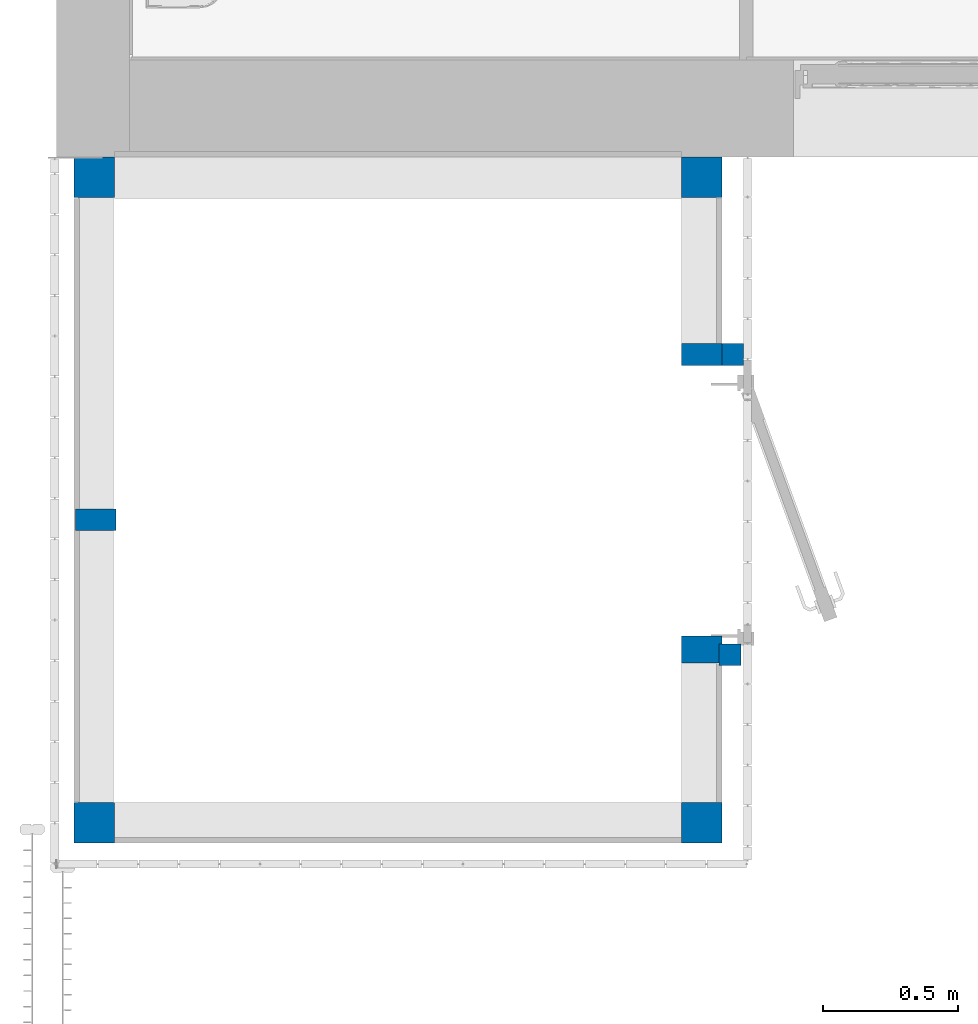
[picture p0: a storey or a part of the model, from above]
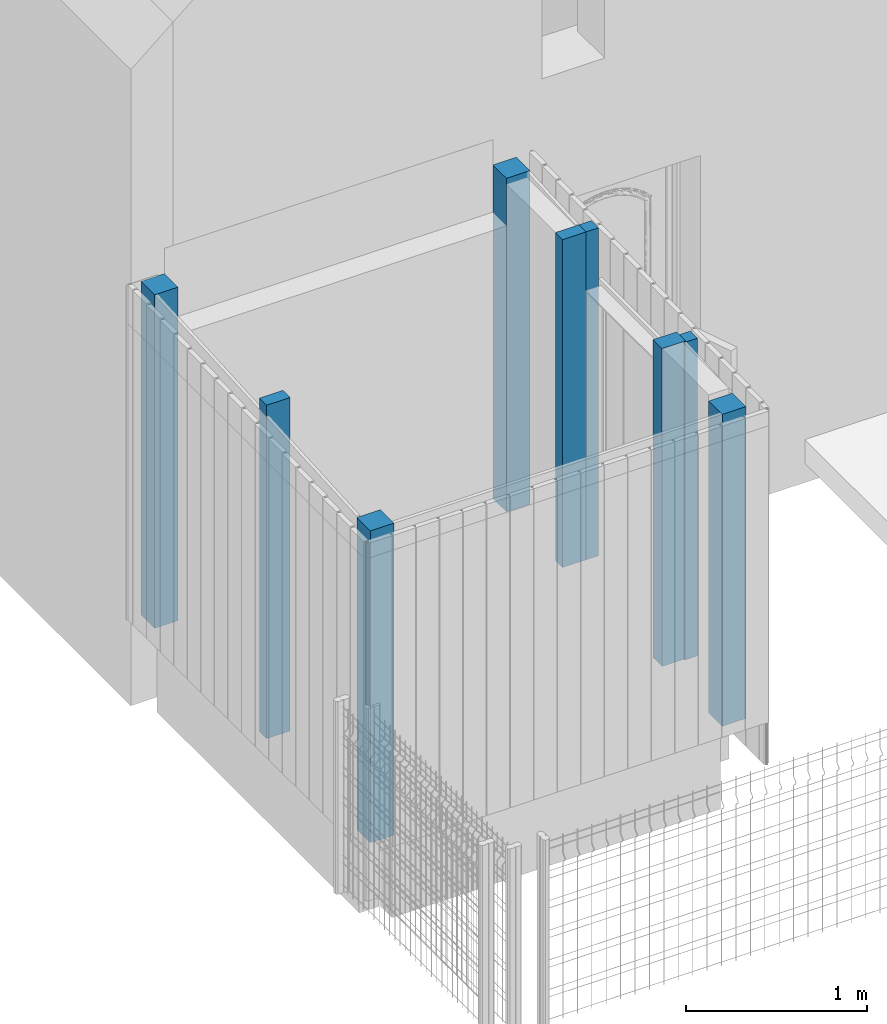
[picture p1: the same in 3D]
Properties of the parts of a building model (IFC2X3)

# File
Description: ViewDefinition [CoordinationView_V2.0]
File name: Affaire n°19.172
Time: 2022-11-25T11:16:12
Written by: The EXPRESS Data Manager Version 5.02.0100.07 : 28 Aug 2013
Made in: 21.0.0.383 - Exporter 21.0.0.383 - Interface utilisateur alternative 21.0.0.383
Comment: STEP Physical File produced by: The EXPRESS Data Manager Version 5.02.0100.07 : 28 Aug 2013 * Module: EDMstepFileFactory/EDMstandAlone * Creation date: Fri Nov 25 11:16:12 2022 * Host: LGB7831 * Database: C:\Users\ROMAIN~1.RIB\AppData\Local\Temp\cd2d28db-151a-48f7-b0e3-fceab26f3357\acbd01e7-b79b-4e43-bebc-0b0fced7cc93\ifc * Database version: 5507 * Database creation date: Fri Nov 25 11:14:17 2022 * Schema: IFC2X3 * Model: DataRepository.ifc * Model creation date: Fri Nov 25 11:14:17 2022 * Header model: DataRepository.ifc_HeaderModel * Header model creation date: Fri Nov 25 11:14:17 2022 * EDMuser: sdai-user * EDMgroup: sdai-group * License ID and type: 5605 : Permanent license. Expiry date: * EDMstepFileFactory options: 020000

# IfcProject, Affaire n°19.172
LongName: Construction de 4 Maisons Individuelles; Phase: Construction

# IfcSite, Surface:931155
RefLatitude: 48, 52, 0, 117187; RefLongitude: 2, 19, 59, 880409; RefElevation: 0 m

# IfcBuilding
Pset_BuildingCommon - NumberOfStoreys: 3

# IfcBuildingStorey: Niveau:Ligne du Niveau (3)
Name | LongName | Elevation (m)
01 RDC | 01 RDC | -1.94916e-14
02 ETG | 02 ETG | 2.72
03 Goutière | 03 Goutière | 3.91

# IfcBuildingElementProxy: Electrical_Distribution_Legrand_Coffrets-isolants-Drivia-pour-de-tableaux-electriques-de-1-a-4-rangees-de-18-modules_FR:coffret DRIVIA 18 modules 1 rangée, Electrical_Distribution_Legrand_Coffrets-isolants-Drivia-pour-de-tableaux-electriques-de-1-a-4-rangees-de-18-modules_FR:coffret DRIVIA 18 modules 1 rangée, 0 V, Monophasé Phase, 2 Fils:699805
In: 01 RDC
Type - Material: Zone d'installation
Type - Pset_BuildingElementProxyCommon - Reference: coffret DRIVIA 18 modules 1 rangée
Type - Pset_ManufacturerTypeInformation - Manufacturer: Legrand
Type - Pset_QuantityTakeOff - Reference: coffret DRIVIA 18 modules 1 rangée
Pset_BuildingElementProxyCommon - sets with these values: 2

# IfcBuildingElementProxy: Frogo 2:Default, Frogo 2:Default:514300
In: 01 RDC
Type - Material: AEG FS Fridge Freezer Bottom Freezer Silver+Stainless Steel Door with Antifingerprint 595 2005 - AEG_FS_Fridge_Freezer_Bottom_Freezer_Silver_Stainless_Steel_Door_with_Antifingerprint_595_2005 - Stainless_Steel
Type - Pset_BuildingElementProxyCommon - Reference: Default
Type - Pset_QuantityTakeOff - Reference: Default
Type - Pset_ProvisionForVoid - Width: 181.356 m; Height: 197.206 m; Depth: 611.124 m
Material: AEG FS Fridge Freezer Bottom Freezer Silver+Stainless Steel Door with Antifingerprint 595 2005 - AEG_FS_Fridge_Freezer_Bottom_Freezer_Silver_Stainless_Steel_Door_with_Antifingerprint_595_2005 - Stainless_Steel, AEG FS Fridge Freezer Bottom Freezer Silver+Stainless Steel Door with Antifingerprint 595 2005 - AEG_FS_Fridge_Freezer_Bottom_Freezer_Silver_Stainless_Steel_Door_with_Antifingerprint_595_2005 - Top_AEG FS Fridge_Freezer Bottom Freezer Silver+Stainless Steel Door with Antifingerprint 59
Pset_BuildingElementProxyCommon - sets with these values: 2

# IfcBuildingElementProxy: Haie 0.25:Haie 0.25 (11)
In: 01 RDC
Type - Pset_BuildingElementProxyCommon - Reference: Haie 0.25
Type - Pset_QuantityTakeOff - Reference: Haie 0.25
Pset_BuildingElementProxyCommon - sets with these values: 2
Name (Haie 0.25:Haie 0.25:...)
514370
514374
514375
514376
514377
514378
514379
514380
514381
514382
514383

# IfcBuildingElementProxy: LL:Default, LL:Default:514303
In: 01 RDC
Type - Material: AEG Free Standing Washer HEC 60 White - AEG_Free_Standing_Washer_HEC_60_White - log_23
Type - Pset_BuildingElementProxyCommon - Reference: Default
Type - Pset_QuantityTakeOff - Reference: Default
Type - Pset_ProvisionForVoid - Width: 182.88 m; Height: 259.08 m; Depth: 184.404 m
Material: AEG Free Standing Washer HEC 60 White - AEG_Free_Standing_Washer_HEC_60_White - log_23, AEG Free Standing Washer HEC 60 White - AEG_Free_Standing_Washer_HEC_60_White - White, AEG Free Standing Washer HEC 60 White - AEG_Free_Standing_Washer_HEC_60_White - Gray, AEG Free Standing Washer HEC 60 White - AEG_Free_Standing_Washer_HEC_60_White - Top_AEG Free_Standing Washer HEC 60 White, AEG Free Standing Washer HEC 60 White - AEG_Free_Standing_Washer_HEC_60_White - Steel, AEG Free Standing Washer HEC 60 White - AEG_Free_Standing_Washer_HEC_60_White - Bottom_AEG Free_Standing Washer HEC 60 White, AEG Free Standing Washer HEC 60 White - AEG_Free_Standing_Washer_HEC_60_White - Black, AEG Free Standing Washer HEC 60 White - AEG_Free_Standing_Washer_HEC_60_White - Dark Gray
Pset_BuildingElementProxyCommon - sets with these values: 2

# IfcBuildingElementProxy: LV:Default (2)
In: 01 RDC
Type - Material: AEG FSBU 60 Dishwasher White - AEG_FSBU_60_Dishwasher_White - White
Type - Pset_BuildingElementProxyCommon - Reference: Default
Type - Pset_QuantityTakeOff - Reference: Default
Material: AEG FSBU 60 Dishwasher White - AEG_FSBU_60_Dishwasher_White - White, AEG FSBU 60 Dishwasher White - AEG_FSBU_60_Dishwasher_White - Top_AEG FSBU 60 Dishwasher White, AEG FSBU 60 Dishwasher White - AEG_FSBU_60_Dishwasher_White - Bottom_AEG FSBU 60 Dishwasher White
Pset_BuildingElementProxyCommon - sets with these values: 2
Name (LV:Default:...)
514301
550132

# IfcBuildingElementProxy: Meuble évier:Meuble évier, Meuble évier:Meuble évier:514305
In: 01 RDC
Type - Material: CabinetFinish
Type - Pset_BuildingElementProxyCommon - Reference: Meuble évier
Type - Pset_QuantityTakeOff - Reference: Meuble évier
Material: CabinetFinish, Default metal, EquipSpace
Pset_BuildingElementProxyCommon - sets with these values: 2
Pset_ProvisionForVoid - Width: 0.56515 m; Height: 0.6096 m; Depth: 0.56515 m

# IfcBuildingElementProxy: Portail pivotant treillis OOBAMBOO:2 vantaux - 3355mm x 1100mm, Portail pivotant treillis OOBAMBOO:2 vantaux - 3355mm x 1100mm:514336
In: 01 RDC
Type - Material: NORMACLO Métal, NORMACLO Butée
Type - Pset_BuildingElementProxyCommon - Reference: 2 vantaux - 3355mm x 1100mm
Type - Pset_ManufacturerTypeInformation - Manufacturer: NORMACLO
Type - Pset_QuantityTakeOff - Reference: 2 vantaux - 3355mm x 1100mm
Material: NORMACLO Métal
Pset_BuildingElementProxyCommon - sets with these values: 2

# IfcBuildingElementProxy: Tiles_Swiss Krono_Placeholder:Tiles_Swiss Krono_Placeholder (5)
In: 01 RDC
Type - Material: Bois - Swiss Krono - OSB 3 - Panneau Anti-Termites 2500x1250x13mm
Type - Pset_BuildingElementProxyCommon - Reference: Tiles_Swiss Krono_Placeholder
Type - Pset_QuantityTakeOff - Reference: Tiles_Swiss Krono_Placeholder
Pset_BuildingElementProxyCommon - sets with these values: 2
Name (Tiles_Swiss Krono_Placeholder:Tiles_Swiss Krono_Placeholder:...) | Width (m) = Height (m) | Depth (m)
908347 | 2.235 | 0.13
917175 | 0.5398 | 0.13
924072 | 0.129219 | 2.095
924377 | 0.5152 | 0.13
1074472 | 0.1525 | 2.095

# IfcColumn: Bois - Bois de construction de dimensions courantes:Poteau bois 15*08 (2)
In: 01 RDC
Type - PredefinedType: COLUMN; Material: Bois - Pin
Type - Pset_ColumnCommon - IsExternal: no; LoadBearing: yes; Reference: Poteau bois 15*08
Type - Pset_QuantityTakeOff - Reference: Poteau bois 15*08
Type - Pset_ReinforcementBarPitchOfColumn - Reference: Poteau bois 15*08
Pset_QuantityTakeOff - sets with these values: 2
Name (Bois - Bois de construction de dimensions courantes:Poteau bois 15*08:...)
514329
910802

# IfcColumn: Bois - Bois de construction de dimensions courantes:Poteau bois 15*10, Bois - Bois de construction de dimensions courantes:Poteau bois 15*10:514325
In: 01 RDC
Type - PredefinedType: COLUMN; Material: Bois - Pin
Type - Pset_ColumnCommon - IsExternal: no; LoadBearing: yes; Reference: Poteau bois 15*10
Type - Pset_QuantityTakeOff - Reference: Poteau bois 15*10
Type - Pset_ReinforcementBarPitchOfColumn - Reference: Poteau bois 15*10
Pset_QuantityTakeOff - sets with these values: 2

# IfcColumn: Bois - Bois de construction de dimensions courantes:Poteau bois 15*15 (4)
In: 01 RDC
Type - PredefinedType: COLUMN; Material: Bois - Pin
Type - Pset_ColumnCommon - IsExternal: no; LoadBearing: yes; Reference: Poteau bois 15*15
Type - Pset_QuantityTakeOff - Reference: Poteau bois 15*15
Type - Pset_ReinforcementBarPitchOfColumn - Reference: Poteau bois 15*15
Pset_QuantityTakeOff - sets with these values: 2
Name (Bois - Bois de construction de dimensions courantes:Poteau bois 15*15:...)
514268
514270
514272
514274

# IfcColumn: Bois - Bois de construction de dimensions courantes:Poteau bois 6*6 (2)
In: 01 RDC
Type - PredefinedType: COLUMN; Material: Bois - Pin
Type - Pset_ColumnCommon - IsExternal: no; LoadBearing: yes; Reference: Poteau bois 6*6
Type - Pset_QuantityTakeOff - Reference: Poteau bois 6*6
Type - Pset_ReinforcementBarPitchOfColumn - Reference: Poteau bois 6*6
Pset_QuantityTakeOff - sets with these values: 2
Name (Bois - Bois de construction de dimensions courantes:Poteau bois 6*6:...)
514327
514331

# IfcCovering: Plafond composé:Plafond 200 + 100 + B.A13 (6)
In: 02 ETG
Type - PredefinedType: CEILING
Type - Pset_CoveringCommon - Reference: Plafond 200 + 100 + B.A13; TotalThickness: 0.31 m
Type - Pset_QuantityTakeOff - Reference: Plafond 200 + 100 + B.A13
Material: Isolant - laine minérale 0.1 m, Maçonnerie - Isolant 0.2 m, Placoplâtre de gypse 0.01 m
Pset_CoveringCommon - Finish: Placoplâtre de gypse;
Name (Plafond composé:Plafond 200 + 100 + B.A13:...)
679123
679951
680673
681739
682132
682653

# IfcCurtainWall: Mur-rideau:1m x 2m (3)
In: 01 RDC
Type - Pset_CurtainWallCommon - IsExternal: no; Reference: 1m x 2m
Type - Pset_QuantityTakeOff - Reference: 1m x 2m
Name (Mur-rideau:1m x 2m:...)
514333
514335
918926

# IfcDistributionPort (12)
Description: Flow
Name | FlowDirection
Port_514301 | SOURCEANDSINK
Port_514301 | SOURCE
Port_514301 | SINK
Port_514303 | SINK
Port_514303 | SOURCE
Port_514303 | SOURCEANDSINK
2 x Port_514304 | SINK
Port_550132 | SINK
Port_550132 | SOURCEANDSINK
Port_550132 | SOURCE
Port_699805 | SOURCEANDSINK

# IfcDoor: Doors_Sliding_PIERRET_Porte-Fenetre_Coulissante_2V:2400 x 2150 mm, Doors_Sliding_PIERRET_Porte-Fenetre_Coulissante_2V:2400 x 2150 mm:853128
In: 01 RDC
Type - OperationType: DOUBLE_DOOR_SLIDING; ParameterTakesPrecedence: no; Sizeable: no; Classification: B2030100 Glazed Doors & Entrances (Uniformat); Material: RAL_7M16ST (2)
Type - Doors_Sliding_PIERRET_Porte-Fenetre_Coulissante_2V:2400 x 2150 mm:853128 - PanelOperation: SLIDING
Type - Pset_DoorCommon - IsExternal: no; Reference: 2400 x 2150 mm
Type - Pset_ManufacturerTypeInformation - Manufacturer: PIERRET
Type - Pset_QuantityTakeOff - Reference: 2400 x 2150 mm
OverallHeight: 2.19 m; OverallWidth: 2.48 m; Material: RAL_7M16ST, Generique - PIERRET - Blanc, Verre - PIERRET - Vitrage, Polyamide - PIERRET - Joint-Intercalaire, Generique - PIERRET - Gris
Pset_DoorCommon - IsExternal: yes

# IfcDoor: Doors_Swing_Bouvet_Single-French-Door_FR:1000 x 2150 mm - Blue (2)
In: 01 RDC
Type - ParameterTakesPrecedence: no; Sizeable: no; Classification: B2030100 (Uniformat); Material: Aluminium - BOUVET - Satiné 7016, Aluminium - BOUVET - Blanc Standard (2), Aluminium - BOUVET - Texturé 7006
Type - Pset_DoorCommon - IsExternal: no; Reference: 1000 x 2150 mm - Blue
Type - Pset_ManufacturerTypeInformation - Manufacturer: BOUVET
Type - Pset_QuantityTakeOff - Reference: 1000 x 2150 mm - Blue
OverallHeight: 2.233 m; OverallWidth: 1.267 m; Material: Aluminium - BOUVET - Blanc Standard, Aluminium - BOUVET - Satiné 7016, Glass, Aluminium - BOUVET - Anodisee
Pset_DoorCommon - IsExternal: yes
Name (Doors_Swing_Bouvet_Single-French-Door_FR:1000 x 2150 mm - Blue:...)
839372
847337

# IfcDoor: Ext. Simple:Lisse - 0.90 m x 2.15 m, Ext. Simple:Lisse - 0.90 m x 2.15 m:928771
In: 01 RDC
Type - OperationType: SINGLE_SWING_RIGHT; ParameterTakesPrecedence: no; Sizeable: no; Material: PVC - Blanc (3)
Type - Ext. Simple:Lisse - 0.90 m x 2.15 m:928771 - PanelOperation: SWINGING
Type - Pset_DoorCommon - IsExternal: no; Reference: Lisse - 0.90 m x 2.15 m; ThermalTransmittance: 5.5617 kg/K/s3
Type - Pset_QuantityTakeOff - Reference: Lisse - 0.90 m x 2.15 m
OverallHeight: 2.2 m; OverallWidth: 1 m; Material: PVC - Blanc
Pset_DoorCommon - IsExternal: yes

# IfcDoor: Int. Simple:PP (0.60 m x 0.8 m), Int. Simple:PP (0.60 m x 0.8 m):706713
In: 01 RDC
Type - ParameterTakesPrecedence: no; Sizeable: no; Material: Bois - Cadre de porte (2), Bois - Panneau de porte, Finition Peinture - Blanc satiné
Type - Pset_DoorCommon - IsExternal: no; Reference: PP (0.60 m x 0.8 m)
Type - Pset_QuantityTakeOff - Reference: PP (0.60 m x 0.8 m)
OverallHeight: 0.835 m; OverallWidth: 0.47 m; Material: Finition Peinture - Blanc satiné, Bois - Panneau de porte, Bois - Cadre de porte

# IfcDoor: Int. Simple:PP (0.73m x 2.04m), Int. Simple:PP (0.73m x 2.04m):514258
In: 01 RDC
Type - ParameterTakesPrecedence: no; Sizeable: no; Material: Finition Peinture - Blanc satiné, Bois - Panneau de porte, Bois - Cadre de porte (2)
Type - Pset_DoorCommon - IsExternal: no; Reference: PP (0.73m x 2.04m); ThermalTransmittance: 3.7021 kg/K/s3
Type - Pset_QuantityTakeOff - Reference: PP (0.73m x 2.04m)
OverallHeight: 2.075 m; OverallWidth: 0.8 m; Material: Finition Peinture - Blanc satiné, Bois - Panneau de porte, Bois - Cadre de porte

# IfcDoor: Int. Simple:PP (0.83m x 2.04m) (2)
Type - ParameterTakesPrecedence: no; Sizeable: no; Material: Bois - Cadre de porte (2), Bois - Panneau de porte, Finition Peinture - Blanc satiné
Type - Pset_DoorCommon - IsExternal: no; Reference: PP (0.83m x 2.04m); ThermalTransmittance: 3.7021 kg/K/s3
Type - Pset_QuantityTakeOff - Reference: PP (0.83m x 2.04m)
OverallHeight: 2.075 m; OverallWidth: 0.9 m; Material: Finition Peinture - Blanc satiné, Bois - Panneau de porte, Bois - Cadre de porte
Name (Int. Simple:PP (0.83m x 2.04m):...) | In
514243 | 01 RDC
732271 | 02 ETG

# IfcDoor: Int. Simple:PP (0.83m x 2.04m), Int. Simple:PP (0.83m x 2.04m):514259
In: 01 RDC
Type - ParameterTakesPrecedence: no; Sizeable: no; Material: Finition Peinture - Blanc satiné, Bois - Cadre de porte (2), Bois - Panneau de porte
Type - Pset_DoorCommon - IsExternal: no; Reference: PP (0.83m x 2.04m); ThermalTransmittance: 3.7021 kg/K/s3
Type - Pset_QuantityTakeOff - Reference: PP (0.83m x 2.04m)
OverallHeight: 2.075 m; OverallWidth: 0.9 m; Material: Finition Peinture - Blanc satiné, Bois - Panneau de porte, Bois - Cadre de porte

# IfcDoor: Int. Simple:Porte pleine parement lisse bois prépeinte (3)
In: 02 ETG
Type - ParameterTakesPrecedence: no; Sizeable: no; Material: Finition Peinture - Blanc satiné, Bois - Cadre de porte (2), Bois - Panneau de porte
Type - Pset_DoorCommon - IsExternal: no; Reference: Porte pleine parement lisse bois prépeinte
Type - Pset_QuantityTakeOff - Reference: Porte pleine parement lisse bois prépeinte
OverallHeight: 2.075 m; OverallWidth: 0.9 m; Material: Finition Peinture - Blanc satiné, Bois - Panneau de porte, Bois - Cadre de porte
Name (Int. Simple:Porte pleine parement lisse bois prépeinte:...) | Reference | sets with these values
514632 | Porte pleine parement lisse bois prépeinte | 2
514636
1084562 | Porte pleine parement lisse bois prépeinte | 2

# IfcDoor: Int. Simple:Porte pleine parement lisse bois prépeinte, Int. Simple:Porte pleine parement lisse bois prépeinte:514656
In: 02 ETG
Type - ParameterTakesPrecedence: no; Sizeable: no; Material: Finition Peinture - Blanc satiné, Bois - Panneau de porte, Bois - Cadre de porte (2)
Type - Pset_DoorCommon - IsExternal: no; Reference: Porte pleine parement lisse bois prépeinte
Type - Pset_QuantityTakeOff - Reference: Porte pleine parement lisse bois prépeinte
OverallHeight: 2.075 m; OverallWidth: 0.9 m; Material: Finition Peinture - Blanc satiné, Bois - Panneau de porte, Bois - Cadre de porte

# IfcDoor: K-LINE RENO-tunnel Porte Entrée 1vt - Créative Arc:K-LINE RENO-tunnel Porte Entrée 1vt - Créative Arc, K-LINE RENO-tunnel Porte Entrée 1vt - Créative Arc:K-LINE RENO-tunnel Porte Entrée 1vt - Créative Arc:878110
In: 01 RDC
Type - ParameterTakesPrecedence: no; Sizeable: no; Classification: B2030110 Exterior Glazed Doors - Aluminum (Uniformat); Material: K.Line Couleur Bleu Clair (2023 T) - ST, K.Line Intemporel Blanc satiné (9016 S) - KQ, Verre sablé
Type - Pset_DoorCommon - IsExternal: no; Reference: K-LINE RENO-tunnel Porte Entrée 1vt - Créative Arc
Type - Pset_ManufacturerTypeInformation - Manufacturer: K.LINE
Type - Pset_QuantityTakeOff - Reference: K-LINE RENO-tunnel Porte Entrée 1vt - Créative Arc
OverallHeight: 2.15 m; OverallWidth: 0.91 m; Material: Verre sablé, K.Line Intemporel Blanc satiné (9016 S) - KQ, K.Line Couleur Bleu Clair (2023 T) - ST, Acier inoxydable AISI 304, K.Line Tendance Gris sablé (2900) - NX, K.Line Vintage Anodisé Argent - AC
Pset_DoorCommon - IsExternal: yes

# IfcDoor: Placard coulissante - 2 panneaux:Placard coulissante - 2 panneaux (5)
In: 02 ETG
Type - OperationType: SLIDING_TO_RIGHT; ParameterTakesPrecedence: no; Sizeable: no; Material: Placard - Profil, Placard - Encadrement, Placard - Porte
Type - Placard coulissante - 2 panneaux:Placard coulissante - 2 panneaux:514622 - PanelOperation: SLIDING
Type - Pset_DoorCommon - IsExternal: no; Reference: Placard coulissante - 2 panneaux; ThermalTransmittance: 3.7021 kg/K/s3
Type - Pset_QuantityTakeOff - Reference: Placard coulissante - 2 panneaux
OverallHeight: 1.98 m; OverallWidth: 1.2 m
Name (Placard coulissante - 2 panneaux:Placard coulissante - 2 panneaux:...)
514622 | Pset_OpeningElementCommon - Reference: Placard coulissante - 2 panneaux; sets with these values: 2
514652
514653
514654
514655

# IfcDoor: Volet coulissant ONDEA 1 vantail simple rail:Bois "CONCEPTION WESTERN UNIQUEMENT" (3)
In: 02 ETG
Type - ParameterTakesPrecedence: no; Sizeable: no; Material: FF bois RAL 5014
Type - Pset_DoorCommon - IsExternal: no; Reference: Bois "CONCEPTION WESTERN UNIQUEMENT"
Type - Pset_ManufacturerTypeInformation - Manufacturer: France Fermetures
Type - Pset_QuantityTakeOff - Reference: Bois "CONCEPTION WESTERN UNIQUEMENT"
OverallHeight: 3.756 m; OverallWidth: 2.59 m
Name (Volet coulissant ONDEA 1 vantail simple rail:Bois "CONCEPTION WESTERN UNIQUEMENT":...)
931392 | Pset_DoorCommon - IsExternal: yes
1081363
1081364

# IfcFlowTerminal: Bac à douche rectangulaire:120 x 90 cm, Bac à douche rectangulaire:120 x 90 cm:514308
In: 01 RDC
Type - Material: Acrylique - Blanc, Métal - Chrome
Type - Pset_QuantityTakeOff - Reference: 120 x 90 cm
Material: Métal - Chrome, Acrylique - Blanc
Pset_DistributionFlowElementCommon - Reference: 120 x 90 cm; sets with these values: 3

# IfcFlowTerminal: Baignoire rectangulaire - Mur:Baignoire rectangulaire - Mur, Baignoire rectangulaire - Mur:Baignoire rectangulaire - Mur:514646
In: 02 ETG
Type - Material: Céramique - Blanche
Type - Pset_QuantityTakeOff - Reference: Baignoire rectangulaire - Mur
Pset_DistributionFlowElementCommon - Reference: Baignoire rectangulaire - Mur; sets with these values: 3

# IfcFlowTerminal: Cuvette réservoir:Cuvette réservoir (2)
Type - Material: Stratifié - Lin, Mat, Porcelaine - Lin
Type - Pset_QuantityTakeOff - Reference: Cuvette réservoir
Material: Porcelaine - Lin, Stratifié - Lin, Mat
Pset_DistributionFlowElementCommon - Reference: Cuvette réservoir; sets with these values: 3
Name (Cuvette réservoir:Cuvette réservoir:...) | In
514306 | 01 RDC
514662 | 02 ETG

# IfcFlowTerminal: Douche - 02:Douche - 02, Douche - 02:Douche - 02:514309
In: 01 RDC
Type - Material: Métal - Chrome poli
Type - Pset_QuantityTakeOff - Reference: Douche - 02
Pset_DistributionFlowElementCommon - Reference: Douche - 02; sets with these values: 3

# IfcFlowTerminal: Evier double:840mm x 560 mm, Evier double:840mm x 560 mm:514304
In: 01 RDC
Type - Material: f26d4e4b_a025_4dbf_b085_30ed485788cf
Type - Pset_QuantityTakeOff - Reference: 840mm x 560 mm
Pset_DistributionFlowElementCommon - Reference: 840mm x 560 mm; sets with these values: 2

# IfcFlowTerminal: Lavabo sur pied:Lavabo sur pied (2)
Type - Material: Métal - Chrome, Porcelaine - Lin (2)
Type - Pset_QuantityTakeOff - Reference: Lavabo sur pied
Material: Porcelaine - Lin, Métal - Chrome
Pset_DistributionFlowElementCommon - Reference: Lavabo sur pied; sets with these values: 3
Name (Lavabo sur pied:Lavabo sur pied:...) | In
514307 | 01 RDC
514644 | 02 ETG

# IfcFlowTerminal: Robinet mural - Douche:#01, Robinet mural - Douche:#01:514310
In: 01 RDC
Type - Material: Métal - Chrome
Type - Pset_QuantityTakeOff - Reference: #01
Pset_DistributionFlowElementCommon - Reference: #01; sets with these values: 3

# IfcFurnishingElement: Armoire de salle de bain - 1 porte miroir:40 x 24 x 64 cm - Blanc, Armoire de salle de bain - 1 porte miroir:40 x 24 x 64 cm - Blanc:514645
In: 02 ETG
Type - Material: Aggloméré - Blanc, Métal - Chrome
Type - Pset_QuantityTakeOff - Reference: 40 x 24 x 64 cm - Blanc
Material: Métal - Chrome, Aggloméré - Blanc

# IfcFurnishingElement: Lit à tête en bois:2000mm x 2100mm (4)
Type - Material: Bois - Teck, Métal - Chrome, Textile - Bleu pâle
Type - Pset_QuantityTakeOff - Reference: 2000mm x 2100mm
Material: Textile - Bleu pâle, Bois - Teck, Métal - Chrome
Name (Lit à tête en bois:2000mm x 2100mm:...) | In
514311 | 01 RDC
514641 | 02 ETG
514642 | 02 ETG
514643 | 02 ETG

# IfcMember: Meneau circulaire:R-30 mm (112)
In: 01 RDC
Type - PredefinedType: MULLION; Material: Aluminium - Vert
Type - Pset_MemberCommon - IsExternal: no; Reference: R-30 mm
Type - Pset_QuantityTakeOff - Reference: R-30 mm
Name (Meneau circulaire:R-30 mm:...) | Span (m)
514448 | 2
514449 | 0.399226
514452 | 0.558478
514453 | 2
514456 | 2
514457 | 2
514458 | 0.549456
514459 | 0.540282
514460 | 2
514461 | 2
514462 | 2
514463 | 0.353584
514464 | 0.34441
514465 | 0.335236
902583 | 0.531107
902584 | 0.521933
902585 | 0.512759
903007 | 0.326061
903008 | 0.316887
903009 | 0.307712
903010 | 2
903011 | 2
903012 | 2
903013 | 2
903014 | 2
903016 | 0.448538
903017 | 0.439364
903018 | 0.430189
903019 | 0.421015
903020 | 0.41184
911406 | 2
911407 | 0.402666
929272 | 2
929273 | 0.15
929274 | 0.15
929275 | 2
514527 | 2
514528 | 0.098614
514552 | 0.258248
514553 | 2
514554 | 2
514555 | 2
514556 | 2
514557 | 2
514558 | 2
514559 | 2
514560 | 2
514561 | 0.199685
514562 | 0.20886
514563 | 0.218034
514564 | 0.227208
514565 | 0.236383
514566 | 0.245557
514567 | 0.254732
514669 | 2
514670 | 0.190511
902988 | 2
902989 | 2
902990 | 2
902991 | 2
902992 | 2
902993 | 2
902994 | 2
902995 | 0.181336
902996 | 0.172162
902997 | 0.162988
902998 | 0.153813
902999 | 0.144639
903000 | 0.135464
903001 | 0.12629
912984 | 2
912985 | 0.117116
926241 | 2
926242 | 0.107941
918928 | 2
918929 | 0.0992256
918955 | 2
918956 | 2
918957 | 2
918958 | 2
918959 | 2
918960 | 2
918961 | 2
918984 | 2
919010 | 2
919011 | 2
919012 | 2
919013 | 2
919014 | 2
919015 | 2
919016 | 2
919057 | 2
928646 | 2
933554 | 0.0992256
933555 | 2
933556 | 0.0992256
933557 | 0.0992256
933558 | 0.0992256
933559 | 0.0992256
933560 | 0.0992256
933561 | 0.0992256
933562 | 0.0992256
933563 | 0.0992256
933564 | 0.0992256
933565 | 0.0992256
933566 | 0.0992256
933567 | 0.0992256
933568 | 0.0992256
933569 | 0.0992256
933570 | 0.0992256
933571 | 0.0992256
933572 | 0.0992256

# IfcOpeningElement: Opening (27)
Name | In
Mur de base:Ext. Enduit 2 + Parpaing 20 + Isolant 14:514209:1 | 01 RDC | Pset_OpeningElementCommon - Reference: Ext. Enduit 2 + Parpaing 20 + Isolant 14; sets with these values: 2
Mur de base:Ext. Enduit 2 + Parpaing 20 + Isolant 14:514209 | 01 RDC | Pset_OpeningElementCommon - Reference: Ext. Enduit 2 + Parpaing 20 + Isolant 14; sets with these values: 2
Int. Simple:Porte pleine parement lisse bois prépeinte:1084562:1 | 02 ETG
Int. Simple:Porte pleine parement lisse bois prépeinte:514656:1 | 02 ETG
Placard coulissante - 2 panneaux:Placard coulissante - 2 panneaux:514652:1 | 02 ETG
Placard coulissante - 2 panneaux:Placard coulissante - 2 panneaux:514653:1 | 02 ETG
Placard coulissante - 2 panneaux:Placard coulissante - 2 panneaux:514655:1 | 02 ETG
Placard coulissante - 2 panneaux:Placard coulissante - 2 panneaux:514654:1 | 02 ETG
Int. Simple:Porte pleine parement lisse bois prépeinte:514636:1 | 02 ETG
Int. Simple:Porte pleine parement lisse bois prépeinte:514632:1 | 02 ETG
Placard coulissante - 2 panneaux:Placard coulissante - 2 panneaux:514622:1 | 02 ETG
Int. Simple:PP (0.83m x 2.04m):732271:1 | 02 ETG
Mur de base:cloison séche - B.A10:514620 | 02 ETG | Pset_OpeningElementCommon - Reference: Placard coulissante - 2 panneaux; sets with these values: 2
Mur de base:cloison séche - B.A10:514621 | 02 ETG | Pset_OpeningElementCommon - Reference: Placard coulissante - 2 panneaux; sets with these values: 2
Mur de base:cloison séche - B.A10:514630 | 02 ETG | Pset_OpeningElementCommon - Reference: Porte pleine parement lisse bois prépeinte; sets with these values: 2
Mur de base:Int. Plâtre 10 mm:639148 | 01 RDC | Pset_OpeningElementCommon - Reference: Int. Plâtre 10 mm; sets with these values: 2
Mur de base:Panneau Triply 30 mm:514413 | 01 RDC
Mur de base:Int. Plâtre 10 mm:663478 | 01 RDC | Pset_OpeningElementCommon - Reference: Int. Plâtre 10 mm; sets with these values: 2
Mur de base:cloison séche - B.A10:1084497 | 02 ETG | Pset_OpeningElementCommon - Reference: Porte pleine parement lisse bois prépeinte; sets with these values: 2
4 x Mur de base:Ext. Enduit 2 + Parpaing 20 + Isolant 14:514209 | 01 RDC
Int. Simple:PP (0.60 m x 0.8 m):706713:1 | 01 RDC
Int. Simple:PP (0.83m x 2.04m):514243:1 | 01 RDC
Int. Simple:PP (0.83m x 2.04m):514259:1 | 01 RDC
Int. Simple:PP (0.73m x 2.04m):514258:1 | 01 RDC

# IfcRailing: Garde-corps:Grillage et Poteaux - 1300 mm (5)
In: 01 RDC
Material: Métal - Peinture verte
Pset_QuantityTakeOff - Reference: Grillage et Poteaux - 1300 mm
Pset_RailingCommon - IsExternal: no; Reference: Grillage et Poteaux - 1300 mm; Height: 1.2192 m
Name (Garde-corps:Grillage et Poteaux - 1300 mm:...)
452555
514339
514346
514353
514362

# IfcRoof: Toit de base:Toit - 200 mm, Toit de base:Toit - 200 mm:514601
In: 03 Goutière
Material: Toit par défaut 0.2 m
Pset_QuantityTakeOff - Reference: Toit - 200 mm
Pset_RoofCommon - IsExternal: yes; Reference: Toit - 200 mm; ProjectedArea: 67.4778 m2; TotalArea: 87.06 m2

# IfcSlab: Sol:Chappe 10 PVC-TX SELECTION 100*1500 2 (4)
Type - PredefinedType: FLOOR; Material: Maçonnerie - Béton 0.005 m
Type - Pset_QuantityTakeOff - Reference: Chappe 10 PVC-TX SELECTION 100*1500 2
Type - Pset_ReinforcementBarPitchOfSlab - Reference: Chappe 10 PVC-TX SELECTION 100*1500 2
Type - Pset_SlabCommon - IsExternal: no; Reference: Chappe 10 PVC-TX SELECTION 100*1500 2
Pset_QuantityTakeOff - sets with these values: 2
Pset_SlabCommon - PitchAngle: 0 deg; LoadBearing: no
Name (Sol:Chappe 10 PVC-TX SELECTION 100*1500 2:...) | In
696257 | 01 RDC
741962 | 02 ETG
742064 | 02 ETG
742115 | 02 ETG

# IfcSlab: Sol:Chappe 10 carrelage 200*200 (2)
In: 01 RDC
Type - PredefinedType: FLOOR; Material: Maçonnerie - Béton avec carrelage 0.005 m, Asphalte, bitume 0.005 m
Type - Pset_QuantityTakeOff - Reference: Chappe 10 carrelage 200*200
Type - Pset_ReinforcementBarPitchOfSlab - Reference: Chappe 10 carrelage 200*200
Type - Pset_SlabCommon - IsExternal: no; Reference: Chappe 10 carrelage 200*200; ThermalTransmittance: 230 kg/K/s3
Pset_QuantityTakeOff - sets with these values: 2
Pset_SlabCommon - PitchAngle: 0 deg; LoadBearing: no
Name (Sol:Chappe 10 carrelage 200*200:...)
696151
696504

# IfcSlab: Sol:Dalle en béton - 16, Sol:Dalle en béton - 16:514584
In: 02 ETG
Type - PredefinedType: FLOOR; Material: Maçonnerie - Béton Blanc 0.16 m
Type - Pset_QuantityTakeOff - Reference: Dalle en béton - 16
Type - Pset_ReinforcementBarPitchOfSlab - Reference: Dalle en béton - 16
Type - Pset_SlabCommon - IsExternal: no; Reference: Dalle en béton - 16
Pset_QuantityTakeOff - sets with these values: 2
Pset_SlabCommon - LoadBearing: no; PitchAngle: 3.5 deg

# IfcSlab: Sol:Dalle en béton - 16 Terasse, Sol:Dalle en béton - 16 Terasse:514318
In: 01 RDC
Type - PredefinedType: FLOOR; Material: Maçonnerie - Béton avec carrelage 0.16 m
Type - Pset_QuantityTakeOff - Reference: Dalle en béton - 16 Terasse
Type - Pset_ReinforcementBarPitchOfSlab - Reference: Dalle en béton - 16 Terasse
Type - Pset_SlabCommon - IsExternal: no; Reference: Dalle en béton - 16 Terasse
Pset_QuantityTakeOff - sets with these values: 2
Pset_SlabCommon - PitchAngle: 0 deg; LoadBearing: no

# IfcSlab: Sol:Dalle en béton - 22, Sol:Dalle en béton - 22:514593
In: 02 ETG
Type - PredefinedType: FLOOR; Material: FF PVC RAL 1015 0.01 m, Béton - Béton précoulé - 35 MPa 0.21 m
Type - Pset_QuantityTakeOff - Reference: Dalle en béton - 22
Type - Pset_ReinforcementBarPitchOfSlab - Reference: Dalle en béton - 22
Type - Pset_SlabCommon - IsExternal: no; Reference: Dalle en béton - 22; ThermalTransmittance: 25.1 kg/K/s3
Pset_QuantityTakeOff - sets with these values: 2
Pset_SlabCommon - LoadBearing: yes; PitchAngle: 0 deg

# IfcSlab: Sol:Dalle en béton - 28, Sol:Dalle en béton - 28:514219
In: 01 RDC
Type - PredefinedType: FLOOR; Material: Maçonnerie - Béton 0.28 m
Type - Pset_QuantityTakeOff - Reference: Dalle en béton - 28
Type - Pset_ReinforcementBarPitchOfSlab - Reference: Dalle en béton - 28
Type - Pset_SlabCommon - IsExternal: no; Reference: Dalle en béton - 28
Pset_QuantityTakeOff - sets with these values: 2
Pset_SlabCommon - LoadBearing: yes; PitchAngle: 0 deg

# IfcStair: Escalier coulé sur place:Monobloc, Escalier coulé sur place:Escalier:514238
In: 01 RDC
Pset_QuantityTakeOff - Reference: Monobloc
Pset_StairCommon - IsExternal: no; Reference: Monobloc; NumberOfRiser: 15; NumberOfTreads: 14; RiserHeight: 0.181333 m; TreadLength: 0.23 m

# IfcWall: Mur de base:Ext. Brique 20, Mur de base:Ext. Brique 20:927312
In: 01 RDC
Type - PredefinedType: STANDARD; Material: Brique, commune 0.2 m
Type - Pset_QuantityTakeOff - Reference: Ext. Brique 20
Type - Pset_ReinforcementBarPitchOfWall - Reference: Ext. Brique 20
Type - Pset_WallCommon - IsExternal: no; Reference: Ext. Brique 20; ThermalTransmittance: 2.7 kg/K/s3
Material: Brique, commune
Pset_QuantityTakeOff - sets with these values: 2
Pset_WallCommon - IsExternal: yes; ExtendToStructure: yes; LoadBearing: no

# IfcWall: Mur de base:Ext. Enduit 2 + Parpaing 20 + Isolant 14, Mur de base:Ext. Enduit 2 + Parpaing 20 + Isolant 14:514213
In: 01 RDC
Type - PredefinedType: STANDARD; Material: Maçonnerie - Enduit 0.02 m, Blocs béton manufacturés 0.2 m, Maçonnerie - Isolant 0.14 m
Type - Pset_QuantityTakeOff - Reference: Ext. Enduit 2 + Parpaing 20 + Isolant 14
Type - Pset_ReinforcementBarPitchOfWall - Reference: Ext. Enduit 2 + Parpaing 20 + Isolant 14
Type - Pset_WallCommon - Reference: Ext. Enduit 2 + Parpaing 20 + Isolant 14; ThermalTransmittance: 6.5 kg/K/s3; IsExternal: no
Pset_QuantityTakeOff - sets with these values: 2
Pset_WallCommon - IsExternal: yes; ExtendToStructure: yes; LoadBearing: yes

# IfcWall: Mur de base:Ext. Parpaing 20 + Isolant 5 + BA10, Mur de base:Ext. Parpaing 20 + Isolant 5 + BA10:514215
In: 01 RDC
Type - PredefinedType: STANDARD; Material: Maçonnerie - Enduit Blanc 0.02 m, Blocs béton manufacturés 0.2 m, Maçonnerie - Isolant 0.04 m, Placoplâtre de gypse 0.01 m
Type - Pset_QuantityTakeOff - Reference: Ext. Parpaing 20 + Isolant 5 + BA10
Type - Pset_ReinforcementBarPitchOfWall - Reference: Ext. Parpaing 20 + Isolant 5 + BA10
Type - Pset_WallCommon - IsExternal: no; Reference: Ext. Parpaing 20 + Isolant 5 + BA10; ThermalTransmittance: 5.90909 kg/K/s3
Pset_QuantityTakeOff - sets with these values: 2
Pset_WallCommon - IsExternal: yes; ExtendToStructure: yes; LoadBearing: yes

# IfcWall: Mur de base:Int. Plâtre 10 mm (2)
In: 02 ETG
Type - PredefinedType: STANDARD; Material: Placoplâtre de gypse 0.01 m
Type - Pset_QuantityTakeOff - Reference: Int. Plâtre 10 mm
Type - Pset_ReinforcementBarPitchOfWall - Reference: Int. Plâtre 10 mm
Type - Pset_WallCommon - IsExternal: no; Reference: Int. Plâtre 10 mm; ThermalTransmittance: 65 kg/K/s3
Pset_QuantityTakeOff - sets with these values: 2
Pset_WallCommon - ExtendToStructure: yes; LoadBearing: no
Name (Mur de base:Int. Plâtre 10 mm:...)
665993
666861

# IfcWall: Mur de base:cloison séche - B.A10, Mur de base:cloison séche - B.A10:1084008
In: 02 ETG
Type - PredefinedType: STANDARD; Material: Mur par défaut 0.05 m
Type - Pset_QuantityTakeOff - Reference: cloison séche - B.A10
Type - Pset_ReinforcementBarPitchOfWall - Reference: cloison séche - B.A10
Type - Pset_WallCommon - IsExternal: no; Reference: cloison séche - B.A10
Pset_QuantityTakeOff - sets with these values: 2
Pset_WallCommon - LoadBearing: no; ExtendToStructure: no

# IfcWallStandardCase: Mur de base:Ext. Brique 4, Mur de base:Ext. Brique 4:716196
In: 01 RDC
Type - PredefinedType: STANDARD; Material: Brique, commune 0.04 m
Type - Pset_QuantityTakeOff - Reference: Ext. Brique 4
Type - Pset_ReinforcementBarPitchOfWall - Reference: Ext. Brique 4
Type - Pset_WallCommon - IsExternal: no; Reference: Ext. Brique 4; ThermalTransmittance: 13.5 kg/K/s3
Pset_QuantityTakeOff - sets with these values: 2
Pset_WallCommon - IsExternal: yes; LoadBearing: no; ExtendToStructure: no

# IfcWallStandardCase: Mur de base:Ext. Enduit 2 + Parpaing 20 + Isolant 14, Mur de base:Ext. Enduit 2 + Parpaing 20 + Isolant 14:514209
In: 01 RDC
Type - PredefinedType: STANDARD; Material: Maçonnerie - Enduit 0.02 m, Blocs béton manufacturés 0.2 m, Maçonnerie - Isolant 0.14 m
Type - Pset_QuantityTakeOff - Reference: Ext. Enduit 2 + Parpaing 20 + Isolant 14
Type - Pset_ReinforcementBarPitchOfWall - Reference: Ext. Enduit 2 + Parpaing 20 + Isolant 14
Type - Pset_WallCommon - Reference: Ext. Enduit 2 + Parpaing 20 + Isolant 14; ThermalTransmittance: 6.5 kg/K/s3; IsExternal: no
Pset_QuantityTakeOff - sets with these values: 2
Pset_WallCommon - IsExternal: yes; ExtendToStructure: yes; LoadBearing: yes

# IfcWallStandardCase: Mur de base:Ext. Parpaing 20 + Isolant 5 + BA10, Mur de base:Ext. Parpaing 20 + Isolant 5 + BA10:514211
In: 01 RDC
Type - PredefinedType: STANDARD; Material: Maçonnerie - Enduit Blanc 0.02 m, Blocs béton manufacturés 0.2 m, Maçonnerie - Isolant 0.04 m, Placoplâtre de gypse 0.01 m
Type - Pset_QuantityTakeOff - Reference: Ext. Parpaing 20 + Isolant 5 + BA10
Type - Pset_ReinforcementBarPitchOfWall - Reference: Ext. Parpaing 20 + Isolant 5 + BA10
Type - Pset_WallCommon - IsExternal: no; Reference: Ext. Parpaing 20 + Isolant 5 + BA10; ThermalTransmittance: 5.90909 kg/K/s3
Pset_QuantityTakeOff - sets with these values: 2
Pset_WallCommon - IsExternal: yes; ExtendToStructure: yes; LoadBearing: yes

# IfcWallStandardCase: Mur de base:Int. Plâtre 10 mm (19)
Type - PredefinedType: STANDARD; Material: Placoplâtre de gypse 0.01 m
Type - Pset_QuantityTakeOff - Reference: Int. Plâtre 10 mm
Type - Pset_ReinforcementBarPitchOfWall - Reference: Int. Plâtre 10 mm
Type - Pset_WallCommon - IsExternal: no; Reference: Int. Plâtre 10 mm; ThermalTransmittance: 65 kg/K/s3
Pset_QuantityTakeOff - sets with these values: 2
Pset_WallCommon - LoadBearing: no
Name (Mur de base:Int. Plâtre 10 mm:...) | In | ExtendToStructure
639148 | 01 RDC | no
639516 | 01 RDC | no
639971 | 01 RDC | no
640216 | 01 RDC | no
663478 | 01 RDC | no
663610 | 01 RDC | no
664158 | 01 RDC | no
664389 | 01 RDC | no
664863 | 01 RDC | no
665699 | 02 ETG | yes
666356 | 02 ETG | yes
686459 | 02 ETG | yes
689505 | 02 ETG | yes
708709 | 01 RDC | no
711563 | 01 RDC | no
711737 | 01 RDC | no
721448 | 02 ETG | yes
722317 | 02 ETG | yes
722781 | 02 ETG | yes

# IfcWallStandardCase: Mur de base:Int. Plâtre 100 mm (2)
In: 03 Goutière
Type - PredefinedType: STANDARD; Material: Isolant - laine minérale 0.3 m
Type - Pset_QuantityTakeOff - Reference: Int. Plâtre 100 mm
Type - Pset_ReinforcementBarPitchOfWall - Reference: Int. Plâtre 100 mm
Type - Pset_WallCommon - IsExternal: no; Reference: Int. Plâtre 100 mm
Pset_QuantityTakeOff - sets with these values: 2
Pset_WallCommon - ExtendToStructure: yes; LoadBearing: no
Name (Mur de base:Int. Plâtre 100 mm:...)
695435
1081520

# IfcWallStandardCase: Mur de base:Int. Plâtre 50 mm (13)
Type - PredefinedType: STANDARD; Material: Mur par défaut 0.05 m
Type - Pset_QuantityTakeOff - Reference: Int. Plâtre 50 mm
Type - Pset_ReinforcementBarPitchOfWall - Reference: Int. Plâtre 50 mm
Type - Pset_WallCommon - IsExternal: no; Reference: Int. Plâtre 50 mm
Pset_QuantityTakeOff - sets with these values: 2
Pset_WallCommon - LoadBearing: no
Name (Mur de base:Int. Plâtre 50 mm:...) | In | ExtendToStructure
514231 | 01 RDC | no
514232 | 01 RDC | yes
514233 | 01 RDC | yes
514236 | 01 RDC | yes
514237 | 01 RDC | yes
514242 | 01 RDC | yes
514647 | 02 ETG | yes
514648 | 02 ETG | yes
514650 | 02 ETG | no
514651 | 02 ETG | no
663897 | 01 RDC | yes
741772 | 02 ETG | yes
1081633 | 03 Goutière | yes

# IfcWallStandardCase: Mur de base:Int. Plâtre 60 mm, Mur de base:Int. Plâtre 60 mm:514241
In: 01 RDC
Type - PredefinedType: STANDARD; Material: Mur par défaut 0.06 m
Type - Pset_QuantityTakeOff - Reference: Int. Plâtre 60 mm
Type - Pset_ReinforcementBarPitchOfWall - Reference: Int. Plâtre 60 mm
Type - Pset_WallCommon - IsExternal: no; Reference: Int. Plâtre 60 mm
Pset_QuantityTakeOff - sets with these values: 2
Pset_WallCommon - LoadBearing: no; ExtendToStructure: no

# IfcWallStandardCase: Mur de base:Int. Polyester 100 mm (11)
Type - PredefinedType: STANDARD; Material: Isolant - laine minérale 0.1 m
Type - Pset_QuantityTakeOff - Reference: Int. Polyester 100 mm
Type - Pset_ReinforcementBarPitchOfWall - Reference: Int. Polyester 100 mm
Type - Pset_WallCommon - IsExternal: no; Reference: Int. Polyester 100 mm
Pset_QuantityTakeOff - sets with these values: 2
Pset_WallCommon - ExtendToStructure: yes; LoadBearing: no
Name (Mur de base:Int. Polyester 100 mm:...) | In
514228 | 01 RDC
514229 | 01 RDC
514230 | 01 RDC
514234 | 01 RDC
514254 | 01 RDC
514255 | 01 RDC
514256 | 01 RDC
514257 | 01 RDC
514664 | 02 ETG
514665 | 02 ETG
664646 | 01 RDC

# IfcWallStandardCase: Mur de base:Int. Polyester 100+10 mm, Mur de base:Int. Polyester 100+10 mm:514663
In: 02 ETG
Type - PredefinedType: STANDARD; Material: Placoplâtre de gypse 0.01 m, Isolant - laine minérale 0.1 m
Type - Pset_QuantityTakeOff - Reference: Int. Polyester 100+10 mm
Type - Pset_ReinforcementBarPitchOfWall - Reference: Int. Polyester 100+10 mm
Type - Pset_WallCommon - IsExternal: no; Reference: Int. Polyester 100+10 mm; ThermalTransmittance: 65 kg/K/s3
Pset_QuantityTakeOff - sets with these values: 2
Pset_WallCommon - ExtendToStructure: yes; LoadBearing: no

# IfcWallStandardCase: Mur de base:Int. Polyester 20 mm (5)
In: 01 RDC
Type - PredefinedType: STANDARD; Material: Maçonnerie - Isolant 0.02 m
Type - Pset_QuantityTakeOff - Reference: Int. Polyester 20 mm
Type - Pset_ReinforcementBarPitchOfWall - Reference: Int. Polyester 20 mm
Type - Pset_WallCommon - IsExternal: no; Reference: Int. Polyester 20 mm
Pset_QuantityTakeOff - sets with these values: 2
Pset_WallCommon - LoadBearing: no
Name (Mur de base:Int. Polyester 20 mm:...) | ExtendToStructure
514277 | yes
514293 | yes
916523 | yes
924364 | yes
1074719 | no

# IfcWallStandardCase: Mur de base:Panneau Triply 30 mm (103)
In: 01 RDC
Type - Material: Résineux, bois de construction 0.03 m
Type - Pset_QuantityTakeOff - Reference: Panneau Triply 30 mm
Type - Pset_ReinforcementBarPitchOfWall - Reference: Panneau Triply 30 mm
Type - Pset_WallCommon - IsExternal: no; Reference: Panneau Triply 30 mm; ThermalTransmittance: 4 kg/K/s3
Pset_QuantityTakeOff - sets with these values: 2
Pset_WallCommon - LoadBearing: no; ExtendToStructure: no
Name (Mur de base:Panneau Triply 30 mm:...)
514427
514426
514425
902582
902581
902580
928732
902574
903186
903188
903190
903192
913759
514421
514420
514419
514418
514417
514416
932810
514414
514413
903182
903183
928731
903185
903187
903189
903191
903193
913757
919999
926243
912986
903224
903222
903220
903218
903216
903214
903212
514671
514568
514570
514572
514574
514576
514578
902525
919998
926244
912987
903225
903223
903221
903219
903217
903215
903213
514672
514569
514571
514573
514575
514577
514579
926312
919477
928648
919059
919036
919034
919032
919030
919028
919026
919024
918986
918969
918971
918973
918975
918977
918979
919009
933573
933574
933575
933576
933577
933578
933579
933580
933581
933582
933583
933584
933585
933586
933587
933588
933589
933590

# IfcWallStandardCase: Mur de base:cloison séche - B.A10 (11)
In: 02 ETG
Type - PredefinedType: STANDARD; Material: Mur par défaut 0.05 m
Type - Pset_QuantityTakeOff - Reference: cloison séche - B.A10
Type - Pset_ReinforcementBarPitchOfWall - Reference: cloison séche - B.A10
Type - Pset_WallCommon - IsExternal: no; Reference: cloison séche - B.A10
Pset_QuantityTakeOff - sets with these values: 2
Pset_WallCommon - LoadBearing: no
Name (Mur de base:cloison séche - B.A10:...) | ExtendToStructure
514617 | yes
514619 | yes
514620 | yes
514621 | yes
514629 | no
514630 | yes
514631 | yes
514633 | yes
514634 | yes
514649 | yes
1084497 | no

# IfcWindow: Fenêtre 1 vantail avec allège fixe vitrée:Fenêtre Alu 1000 x 1850 mm - Bleue (2)
In: 02 ETG
Type - ParameterTakesPrecedence: no; Sizeable: no; Classification: B2020100 B2020100 B2020100 B2020100 (Uniformat); Material: Aluminium - BOUVET - Blanc Standard (2), Aluminium - BOUVET - Satiné 7016, Aluminium - BOUVET - Texturé 7006
Type - Pset_ManufacturerTypeInformation - Manufacturer: BOUVET
Type - Pset_QuantityTakeOff - Reference: Fenêtre Alu 1000 x 1850 mm - Bleue
Type - Pset_WindowCommon - IsExternal: no; Reference: Fenêtre Alu 1000 x 1850 mm - Bleue
OverallHeight: 1.931 m; OverallWidth: 1.267 m; Material: Aluminium - BOUVET - Blanc Standard, Aluminium - BOUVET - Satiné 7016, Glass
Pset_WindowCommon - IsExternal: yes
Name (Fenêtre 1 vantail avec allège fixe vitrée:Fenêtre Alu 1000 x 1850 mm - Bleue:...)
514659
514661

# IfcWindow: Fenêtre 1 vantail avec allège fixe vitrée:Fenêtre Alu 1000 x 1850 mm - Bleue, Fenêtre 1 vantail avec allège fixe vitrée:Fenêtre Alu 1000 x 1850 mm - Bleue:514658
In: 02 ETG
Type - ParameterTakesPrecedence: no; Sizeable: no; Classification: B2020100 B2020100 B2020100 B2020100 (Uniformat); Material: Aluminium - BOUVET - Blanc Standard (2), Aluminium - BOUVET - Texturé 7006, Aluminium - BOUVET - Satiné 7016
Type - Pset_ManufacturerTypeInformation - Manufacturer: BOUVET
Type - Pset_QuantityTakeOff - Reference: Fenêtre Alu 1000 x 1850 mm - Bleue
Type - Pset_WindowCommon - IsExternal: no; Reference: Fenêtre Alu 1000 x 1850 mm - Bleue
OverallHeight: 1.931 m; OverallWidth: 1.267 m; Material: Aluminium - BOUVET - Blanc Standard, Aluminium - BOUVET - Satiné 7016, Glass
Pset_WindowCommon - IsExternal: yes

# IfcWindow: Fenêtre 1 vantail avec allège fixe vitrée:Fenêtre Alu 40 x 1850 mm - Bleue, Fenêtre 1 vantail avec allège fixe vitrée:Fenêtre Alu 40 x 1850 mm - Bleue:514660
In: 02 ETG
Type - ParameterTakesPrecedence: no; Sizeable: no; Classification: B2020100 B2020100 B2020100 B2020100 (Uniformat); Material: Aluminium - BOUVET - Satiné 7016, Aluminium - BOUVET - Blanc Standard (2), Aluminium - BOUVET - Texturé 7006
Type - Pset_ManufacturerTypeInformation - Manufacturer: BOUVET
Type - Pset_QuantityTakeOff - Reference: Fenêtre Alu 40 x 1850 mm - Bleue
Type - Pset_WindowCommon - IsExternal: no; Reference: Fenêtre Alu 40 x 1850 mm - Bleue
OverallHeight: 1.931 m; OverallWidth: 0.667 m; Material: Aluminium - BOUVET - Blanc Standard, Aluminium - BOUVET - Satiné 7016, Glass
Pset_WindowCommon - IsExternal: yes

# IfcWindow: Fenêtre de toit:Fenêtre de toit, Fenêtre de toit:Fenêtre de toit:514657
In: 03 Goutière
Type - ParameterTakesPrecedence: no; Sizeable: no; Material: Fenêtre de toit - Cadre, <Unnamed>
Type - Pset_QuantityTakeOff - Reference: Fenêtre de toit
Type - Pset_WindowCommon - IsExternal: no; Reference: Fenêtre de toit; ThermalTransmittance: 3.6886 kg/K/s3
OverallHeight: 0.245 m; OverallWidth: 0.9 m; Material: Fenêtre de toit - Cadre, Fenêtre - Vitrage
Pset_WindowCommon - IsExternal: yes

# IfcStairFlightType, no part of this type: Volée monobloc:Profondeur de structure 80 mm
PredefinedType: WINDER
Pset_QuantityTakeOff - Reference: Profondeur de structure 80 mm
Pset_StairFlightCommon - Reference: Profondeur de structure 80 mm
